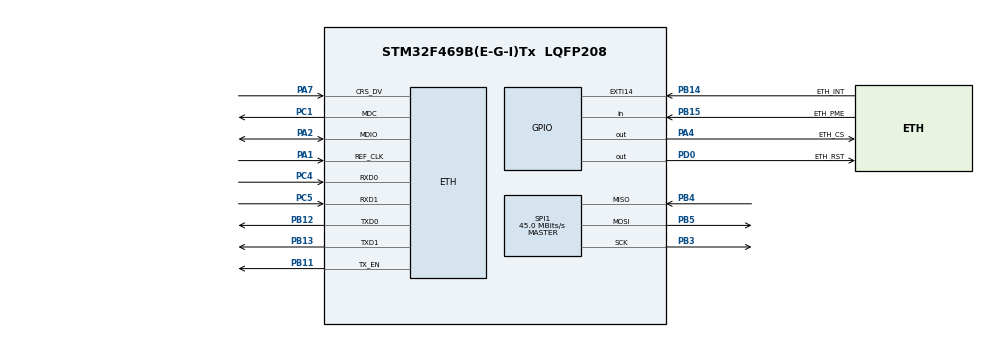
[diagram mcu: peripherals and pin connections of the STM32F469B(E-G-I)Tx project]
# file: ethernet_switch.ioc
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ETH.MediaInterface=HAL_ETH_RMII_MODE
ETH.RxMode=ETH_RXINTERRUPT_MODE
Mcu.Family=STM32F4
Mcu.Name=STM32F469B(E-G-I)Tx
Mcu.Package=LQFP208
NVIC.ETH_IRQn=true\:0\:0\:false\:false\:true\:true\:true\:true
NVIC.PriorityGroup=NVIC_PRIORITYGROUP_4
PA1.Mode=RMII
PA1.Signal=ETH_REF_CLK
PA2.Mode=RMII
PA2.Signal=ETH_MDIO
PA4.GPIO_Label=ETH_CS
PA4.GPIO_Speed=GPIO_SPEED_FREQ_VERY_HIGH
PA4.PinState=GPIO_PIN_SET
PA4.Signal=GPIO_Output
PA7.Mode=RMII
PA7.Signal=ETH_CRS_DV
PB11.Mode=RMII
PB11.Signal=ETH_TX_EN
PB12.Mode=RMII
PB12.Signal=ETH_TXD0
PB13.Mode=RMII
PB13.Signal=ETH_TXD1
PB14.GPIO_Label=ETH_INT
PB14.Signal=GPXTI14
PB15.GPIO_Label=ETH_PME
PB15.Signal=GPIO_Input
PB3.Mode=Full_Duplex_Master
PB3.Signal=SPI1_SCK
PB4.Mode=Full_Duplex_Master
PB4.Signal=SPI1_MISO
PB5.Mode=Full_Duplex_Master
PB5.Signal=SPI1_MOSI
PC1.Mode=RMII
PC1.Signal=ETH_MDC
PC4.Mode=RMII
PC4.Signal=ETH_RXD0
PC5.Mode=RMII
PC5.Signal=ETH_RXD1
PD0.GPIO_Label=ETH_RST
PD0.Signal=GPIO_Output
ProjectManager.HeapSize=0x200
ProjectManager.StackSize=0x400
ProjectManager.TargetToolchain=EWARM V8.50
RCC.AHBFreq_Value=180000000
RCC.APB1CLKDivider=RCC_HCLK_DIV4
RCC.APB1Freq_Value=45000000
RCC.APB1TimFreq_Value=90000000
RCC.APB2CLKDivider=RCC_HCLK_DIV2
RCC.APB2Freq_Value=90000000
RCC.APB2TimFreq_Value=180000000
RCC.CortexFreq_Value=180000000
RCC.HCLKFreq_Value=180000000
RCC.PLLM=8
RCC.PLLN=180
RCC.SYSCLKFreq_VALUE=180000000
RCC.SYSCLKSource=RCC_SYSCLKSOURCE_PLLCLK
RCC.USBFreq_Value=90000000
RCC.VCOOutputFreq_Value=360000000
SPI1.CalculateBaudRate=45.0 MBits/s
SPI1.Direction=SPI_DIRECTION_2LINES
SPI1.Mode=SPI_MODE_MASTER
SPI1.VirtualType=VM_MASTER
board=custom

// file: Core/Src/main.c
/* USER CODE BEGIN Header */
/**
  ******************************************************************************
  * @file           : main.c
  * @brief          : Main program body
  ******************************************************************************
  * @attention
  *
  * Copyright (c) 2026 STMicroelectronics.
  * All rights reserved.
  *
  * This software is licensed under terms that can be found in the LICENSE file
  * in the root directory of this software component.
  * If no LICENSE file comes with this software, it is provided AS-IS.
  *
  ******************************************************************************
  */
/* USER CODE END Header */
#include "main.h"
#include "cmsis_os.h"
#include "lwip.h"
#include "usb_device.h"

/* USER CODE BEGIN Includes */
#include "kszspi.h"
#include "config.h"
/* USER CODE END Includes */

/* USER CODE BEGIN PD */
#define MIB_RX_BYTE_CNT 0x80
#define MIB_TX_BYTE_CNT 0x81
/* USER CODE END PD */

SPI_HandleTypeDef hspi1;
DMA_HandleTypeDef hdma_spi1_tx;
DMA_HandleTypeDef hdma_spi1_rx;

osThreadId MainTaskHandle;
osThreadId WebUITaskHandle;
osThreadId MQTTTaskHandle;
osMessageQId mqttPublishQueueHandle;

void SystemClock_Config(void);
static void MX_GPIO_Init(void);
static void MX_DMA_Init(void);
static void MX_SPI1_Init(void);
void StartDefaultTask(void const * argument);
void StartTask02(void const * argument);
void StartTask03(void const * argument);

int main(void)
{

  /* MCU Configuration--------------------------------------------------------*/

  /* Reset of all peripherals, Initializes the Flash interface and the Systick. */
  HAL_Init();

  /* Configure the system clock */
  SystemClock_Config();

  /* Initialize all configured peripherals */
  MX_GPIO_Init();
  MX_DMA_Init();
  MX_SPI1_Init();
  /* USER CODE BEGIN 2 */
  Config_Init();
  /* USER CODE END 2 */

  /* Create the queue(s) */
  /* definition and creation of mqttPublishQueue */
  osMessageQDef(mqttPublishQueue, 16, uint32_t);
  mqttPublishQueueHandle = osMessageCreate(osMessageQ(mqttPublishQueue), NULL);

  /* Create the thread(s) */
  /* definition and creation of MainTask */
  osThreadDef(MainTask, StartDefaultTask, osPriorityNormal, 0, 256);
  MainTaskHandle = osThreadCreate(osThread(MainTask), NULL);

  /* definition and creation of WebUITask */
  osThreadDef(WebUITask, StartTask02, osPriorityIdle, 0, 1024);
  WebUITaskHandle = osThreadCreate(osThread(WebUITask), NULL);

  /* definition and creation of MQTTTask */
  osThreadDef(MQTTTask, StartTask03, osPriorityIdle, 0, 2048);
  MQTTTaskHandle = osThreadCreate(osThread(MQTTTask), NULL);

  /* Start scheduler */
  osKernelStart();

  /* We should never get here as control is now taken by the scheduler */

  /* Infinite loop */
  while (1)
  {

  }
}

void SystemClock_Config(void)
{
  RCC_OscInitTypeDef RCC_OscInitStruct = {0};
  RCC_ClkInitTypeDef RCC_ClkInitStruct = {0};

  /** Configure the main internal regulator output voltage
  */
  __HAL_RCC_PWR_CLK_ENABLE();
  __HAL_PWR_VOLTAGESCALING_CONFIG(PWR_REGULATOR_VOLTAGE_SCALE3);

  /** Initializes the RCC Oscillators according to the specified parameters
  * in the RCC_OscInitTypeDef structure.
  */
  RCC_OscInitStruct.OscillatorType = RCC_OSCILLATORTYPE_HSE;
  RCC_OscInitStruct.HSEState = RCC_HSE_BYPASS;
  RCC_OscInitStruct.PLL.PLLState = RCC_PLL_ON;
  RCC_OscInitStruct.PLL.PLLSource = RCC_PLLSOURCE_HSE;
  RCC_OscInitStruct.PLL.PLLM = 15;
  RCC_OscInitStruct.PLL.PLLN = 144;
  RCC_OscInitStruct.PLL.PLLP = RCC_PLLP_DIV2;
  RCC_OscInitStruct.PLL.PLLQ = 5;
  RCC_OscInitStruct.PLL.PLLR = 2;
  if (HAL_RCC_OscConfig(&RCC_OscInitStruct) != HAL_OK)
  {
    Error_Handler();
  }

  /** Initializes the CPU, AHB and APB buses clocks
  */
  RCC_ClkInitStruct.ClockType = RCC_CLOCKTYPE_HCLK|RCC_CLOCKTYPE_SYSCLK
                              |RCC_CLOCKTYPE_PCLK1|RCC_CLOCKTYPE_PCLK2;
  RCC_ClkInitStruct.SYSCLKSource = RCC_SYSCLKSOURCE_PLLCLK;
  RCC_ClkInitStruct.AHBCLKDivider = RCC_SYSCLK_DIV1;
  RCC_ClkInitStruct.APB1CLKDivider = RCC_HCLK_DIV4;
  RCC_ClkInitStruct.APB2CLKDivider = RCC_HCLK_DIV2;

  if (HAL_RCC_ClockConfig(&RCC_ClkInitStruct, FLASH_LATENCY_3) != HAL_OK)
  {
    Error_Handler();
  }
}

static void MX_SPI1_Init(void)
{

  /* SPI1 parameter configuration*/
  hspi1.Instance = SPI1;
  hspi1.Init.Mode = SPI_MODE_MASTER;
  hspi1.Init.Direction = SPI_DIRECTION_2LINES;
  hspi1.Init.DataSize = SPI_DATASIZE_8BIT;
  hspi1.Init.CLKPolarity = SPI_POLARITY_LOW;
  hspi1.Init.CLKPhase = SPI_PHASE_1EDGE;
  hspi1.Init.NSS = SPI_NSS_SOFT;
  hspi1.Init.BaudRatePrescaler = SPI_BAUDRATEPRESCALER_2;
  hspi1.Init.FirstBit = SPI_FIRSTBIT_MSB;
  hspi1.Init.TIMode = SPI_TIMODE_DISABLE;
  hspi1.Init.CRCCalculation = SPI_CRCCALCULATION_DISABLE;
  hspi1.Init.CRCPolynomial = 10;
  if (HAL_SPI_Init(&hspi1) != HAL_OK)
  {
    Error_Handler();
  }

}

static void MX_DMA_Init(void)
{

  /* DMA controller clock enable */
  __HAL_RCC_DMA2_CLK_ENABLE();

  /* DMA interrupt init */
  /* DMA2_Stream0_IRQn interrupt configuration */
  HAL_NVIC_SetPriority(DMA2_Stream0_IRQn, 5, 0);
  HAL_NVIC_EnableIRQ(DMA2_Stream0_IRQn);
  /* DMA2_Stream3_IRQn interrupt configuration */
  HAL_NVIC_SetPriority(DMA2_Stream3_IRQn, 5, 0);
  HAL_NVIC_EnableIRQ(DMA2_Stream3_IRQn);

}

static void MX_GPIO_Init(void)
{
  GPIO_InitTypeDef GPIO_InitStruct = {0};

  /* GPIO Ports Clock Enable */
  __HAL_RCC_GPIOE_CLK_ENABLE();
  __HAL_RCC_GPIOI_CLK_ENABLE();
  __HAL_RCC_GPIOC_CLK_ENABLE();
  __HAL_RCC_GPIOF_CLK_ENABLE();
  __HAL_RCC_GPIOH_CLK_ENABLE();
  __HAL_RCC_GPIOA_CLK_ENABLE();
  __HAL_RCC_GPIOB_CLK_ENABLE();
  __HAL_RCC_GPIOJ_CLK_ENABLE();
  __HAL_RCC_GPIOG_CLK_ENABLE();
  __HAL_RCC_GPIOD_CLK_ENABLE();
  __HAL_RCC_GPIOK_CLK_ENABLE();

  /*Configure GPIO pin Output Level */
  HAL_GPIO_WritePin(SPI_CS_GPIO_Port, SPI_CS_Pin, GPIO_PIN_SET);

  /*Configure GPIO pin Output Level */
  HAL_GPIO_WritePin(SW_RST_GPIO_Port, SW_RST_Pin, GPIO_PIN_RESET);

  /*Configure GPIO pins : PE2 PE3 PE4 PE5
                           PE6 PE7 PE8 PE9
                           PE10 PE11 PE12 PE13
                           PE14 PE15 PE0 PE1 */
  GPIO_InitStruct.Pin = GPIO_PIN_2|GPIO_PIN_3|GPIO_PIN_4|GPIO_PIN_5
                          |GPIO_PIN_6|GPIO_PIN_7|GPIO_PIN_8|GPIO_PIN_9
                          |GPIO_PIN_10|GPIO_PIN_11|GPIO_PIN_12|GPIO_PIN_13
                          |GPIO_PIN_14|GPIO_PIN_15|GPIO_PIN_0|GPIO_PIN_1;
  GPIO_InitStruct.Mode = GPIO_MODE_ANALOG;
  GPIO_InitStruct.Pull = GPIO_NOPULL;
  HAL_GPIO_Init(GPIOE, &GPIO_InitStruct);

  /*Configure GPIO pins : PI8 PI9 PI10 PI11
                           PI12 PI13 PI14 PI15
                           PI0 PI1 PI2 PI3
                           PI4 PI5 PI6 PI7 */
  GPIO_InitStruct.Pin = GPIO_PIN_8|GPIO_PIN_9|GPIO_PIN_10|GPIO_PIN_11
                          |GPIO_PIN_12|GPIO_PIN_13|GPIO_PIN_14|GPIO_PIN_15
                          |GPIO_PIN_0|GPIO_PIN_1|GPIO_PIN_2|GPIO_PIN_3
                          |GPIO_PIN_4|GPIO_PIN_5|GPIO_PIN_6|GPIO_PIN_7;
  GPIO_InitStruct.Mode = GPIO_MODE_ANALOG;
  GPIO_InitStruct.Pull = GPIO_NOPULL;
  HAL_GPIO_Init(GPIOI, &GPIO_InitStruct);

  /*Configure GPIO pins : PC13 PC14 PC15 PC0
                           PC2 PC3 PC6 PC7
                           PC8 PC9 PC10 PC11
                           PC12 */
  GPIO_InitStruct.Pin = GPIO_PIN_13|GPIO_PIN_14|GPIO_PIN_15|GPIO_PIN_0
                          |GPIO_PIN_2|GPIO_PIN_3|GPIO_PIN_6|GPIO_PIN_7
                          |GPIO_PIN_8|GPIO_PIN_9|GPIO_PIN_10|GPIO_PIN_11
                          |GPIO_PIN_12;
  GPIO_InitStruct.Mode = GPIO_MODE_ANALOG;
  GPIO_InitStruct.Pull = GPIO_NOPULL;
  HAL_GPIO_Init(GPIOC, &GPIO_InitStruct);

  /*Configure GPIO pins : PF0 PF1 PF2 PF3
                           PF4 PF5 PF6 PF7
                           PF8 PF9 PF10 PF11
                           PF12 PF13 PF14 PF15 */
  GPIO_InitStruct.Pin = GPIO_PIN_0|GPIO_PIN_1|GPIO_PIN_2|GPIO_PIN_3
                          |GPIO_PIN_4|GPIO_PIN_5|GPIO_PIN_6|GPIO_PIN_7
                          |GPIO_PIN_8|GPIO_PIN_9|GPIO_PIN_10|GPIO_PIN_11
                          |GPIO_PIN_12|GPIO_PIN_13|GPIO_PIN_14|GPIO_PIN_15;
  GPIO_InitStruct.Mode = GPIO_MODE_ANALOG;
  GPIO_InitStruct.Pull = GPIO_NOPULL;
  HAL_GPIO_Init(GPIOF, &GPIO_InitStruct);

  /*Configure GPIO pins : PA0 PA3 PA5 PA6
                           PA8 PA9 PA10 PA13
                           PA14 PA15 */
  GPIO_InitStruct.Pin = GPIO_PIN_0|GPIO_PIN_3|GPIO_PIN_5|GPIO_PIN_6
                          |GPIO_PIN_8|GPIO_PIN_9|GPIO_PIN_10|GPIO_PIN_13
                          |GPIO_PIN_14|GPIO_PIN_15;
  GPIO_InitStruct.Mode = GPIO_MODE_ANALOG;
  GPIO_InitStruct.Pull = GPIO_NOPULL;
  HAL_GPIO_Init(GPIOA, &GPIO_InitStruct);

  /*Configure GPIO pins : PH2 PH3 PH4 PH5
                           PH6 PH7 PH8 PH9
                           PH10 PH11 PH12 PH13
                           PH14 PH15 */
  GPIO_InitStruct.Pin = GPIO_PIN_2|GPIO_PIN_3|GPIO_PIN_4|GPIO_PIN_5
                          |GPIO_PIN_6|GPIO_PIN_7|GPIO_PIN_8|GPIO_PIN_9
                          |GPIO_PIN_10|GPIO_PIN_11|GPIO_PIN_12|GPIO_PIN_13
                          |GPIO_PIN_14|GPIO_PIN_15;
  GPIO_InitStruct.Mode = GPIO_MODE_ANALOG;
  GPIO_InitStruct.Pull = GPIO_NOPULL;
  HAL_GPIO_Init(GPIOH, &GPIO_InitStruct);

  /*Configure GPIO pin : SPI_CS_Pin */
  GPIO_InitStruct.Pin = SPI_CS_Pin;
  GPIO_InitStruct.Mode = GPIO_MODE_OUTPUT_PP;
  GPIO_InitStruct.Pull = GPIO_NOPULL;
  GPIO_InitStruct.Speed = GPIO_SPEED_FREQ_VERY_HIGH;
  HAL_GPIO_Init(SPI_CS_GPIO_Port, &GPIO_InitStruct);

  /*Configure GPIO pins : PB0 PB1 PB2 PB10
                           PB6 PB7 PB8 PB9 */
  GPIO_InitStruct.Pin = GPIO_PIN_0|GPIO_PIN_1|GPIO_PIN_2|GPIO_PIN_10
                          |GPIO_PIN_6|GPIO_PIN_7|GPIO_PIN_8|GPIO_PIN_9;
  GPIO_InitStruct.Mode = GPIO_MODE_ANALOG;
  GPIO_InitStruct.Pull = GPIO_NOPULL;
  HAL_GPIO_Init(GPIOB, &GPIO_InitStruct);

  /*Configure GPIO pins : PJ0 PJ1 PJ2 PJ3
                           PJ4 PJ5 PJ12 PJ13
                           PJ14 PJ15 */
  GPIO_InitStruct.Pin = GPIO_PIN_0|GPIO_PIN_1|GPIO_PIN_2|GPIO_PIN_3
                          |GPIO_PIN_4|GPIO_PIN_5|GPIO_PIN_12|GPIO_PIN_13
                          |GPIO_PIN_14|GPIO_PIN_15;
  GPIO_InitStruct.Mode = GPIO_MODE_ANALOG;
  GPIO_InitStruct.Pull = GPIO_NOPULL;
  HAL_GPIO_Init(GPIOJ, &GPIO_InitStruct);

  /*Configure GPIO pins : PG0 PG1 PG2 PG3
                           PG4 PG5 PG6 PG7
                           PG8 PG9 PG10 PG11
                           PG12 PG13 PG14 PG15 */
  GPIO_InitStruct.Pin = GPIO_PIN_0|GPIO_PIN_1|GPIO_PIN_2|GPIO_PIN_3
                          |GPIO_PIN_4|GPIO_PIN_5|GPIO_PIN_6|GPIO_PIN_7
                          |GPIO_PIN_8|GPIO_PIN_9|GPIO_PIN_10|GPIO_PIN_11
                          |GPIO_PIN_12|GPIO_PIN_13|GPIO_PIN_14|GPIO_PIN_15;
  GPIO_InitStruct.Mode = GPIO_MODE_ANALOG;
  GPIO_InitStruct.Pull = GPIO_NOPULL;
  HAL_GPIO_Init(GPIOG, &GPIO_InitStruct);

  /*Configure GPIO pin : SW_INT_Pin */
  GPIO_InitStruct.Pin = SW_INT_Pin;
  GPIO_InitStruct.Mode = GPIO_MODE_IT_RISING;
  GPIO_InitStruct.Pull = GPIO_NOPULL;
  HAL_GPIO_Init(SW_INT_GPIO_Port, &GPIO_InitStruct);

  /*Configure GPIO pin : SW_PME_Pin */
  GPIO_InitStruct.Pin = SW_PME_Pin;
  GPIO_InitStruct.Mode = GPIO_MODE_INPUT;
  GPIO_InitStruct.Pull = GPIO_NOPULL;
  HAL_GPIO_Init(SW_PME_GPIO_Port, &GPIO_InitStruct);

  /*Configure GPIO pins : PD8 PD9 PD10 PD11
                           PD12 PD13 PD14 PD15
                           PD1 PD2 PD3 PD4
                           PD5 PD6 PD7 */
  GPIO_InitStruct.Pin = GPIO_PIN_8|GPIO_PIN_9|GPIO_PIN_10|GPIO_PIN_11
                          |GPIO_PIN_12|GPIO_PIN_13|GPIO_PIN_14|GPIO_PIN_15
                          |GPIO_PIN_1|GPIO_PIN_2|GPIO_PIN_3|GPIO_PIN_4
                          |GPIO_PIN_5|GPIO_PIN_6|GPIO_PIN_7;
  GPIO_InitStruct.Mode = GPIO_MODE_ANALOG;
  GPIO_InitStruct.Pull = GPIO_NOPULL;
  HAL_GPIO_Init(GPIOD, &GPIO_InitStruct);

  /*Configure GPIO pin : SW_RST_Pin */
  GPIO_InitStruct.Pin = SW_RST_Pin;
  GPIO_InitStruct.Mode = GPIO_MODE_OUTPUT_PP;
  GPIO_InitStruct.Pull = GPIO_NOPULL;
  GPIO_InitStruct.Speed = GPIO_SPEED_FREQ_LOW;
  HAL_GPIO_Init(SW_RST_GPIO_Port, &GPIO_InitStruct);

  /*Configure GPIO pins : PK3 PK4 PK5 PK6
                           PK7 */
  GPIO_InitStruct.Pin = GPIO_PIN_3|GPIO_PIN_4|GPIO_PIN_5|GPIO_PIN_6
                          |GPIO_PIN_7;
  GPIO_InitStruct.Mode = GPIO_MODE_ANALOG;
  GPIO_InitStruct.Pull = GPIO_NOPULL;
  HAL_GPIO_Init(GPIOK, &GPIO_InitStruct);

}

void StartDefaultTask(void const * argument)
{
  /* init code for USB_DEVICE */
  MX_USB_DEVICE_Init();

  /* init code for LWIP */
  MX_LWIP_Init();
  /* USER CODE BEGIN 5 */
  if (KSZ_SPI_Init() == 1) {

  } else {

  }

  uint16_t speed = 0;
  uint8_t duplex = 0;
  uint8_t link_status = 0;
  uint64_t rx_bytes = 0;
  uint64_t tx_bytes = 0;

  /* Infinite loop */
  for(;;)
  {

    char *json_buffer = (char *)pvPortMalloc(512);

    if (json_buffer != NULL) {
      int offset = 0;

      offset += snprintf(json_buffer + offset, sizeof(json_buffer) - offset, "{");

      for (int i = 1; i < 8; i++) {
        link_status = KSZ_GetPortStatus(i, &speed, &duplex);
        if (link_status == 1) {
          rx_bytes = KSZ_ReadMIB(i, MIB_RX_BYTE_CNT);
          tx_bytes = KSZ_ReadMIB(i, MIB_TX_BYTE_CNT);
        } else {
          rx_bytes = 0;
          tx_bytes = 0;
        }
        offset += snprintf(json_buffer + offset, sizeof(json_buffer) - offset,
                     "\"port_%d\":{\"link\":%d,\"speed\":%d,\"duplex\":%d,\"rx\":%llu,\"tx\":%llu}%s",
                     i, link_status, speed, duplex, rx_bytes, tx_bytes,
                     (i == 7) ? "" : ",");
      }
      snprintf(json_buffer + offset, sizeof(json_buffer) - offset, "}");

      char *pointer_to_send = json_buffer;

      if (xQueueSend(mqttPublishQueueHandle, &json_buffer, pdMS_TO_TICKS(10)) != pdPASS) {
        vPortFree(json_buffer);
      }
    }

    osDelay(1000);
  }
  /* USER CODE END 5 */
}

void StartTask02(void const * argument)
{
  for(;;)
  {
    osDelay(1);
  }
}

void StartTask03(void const * argument)
{
  /* USER CODE BEGIN StartTask03 */
  mqtt_client_t *client = mqtt_client_new();

  ip_addr_t broker_ip;
  struct mqtt_connect_client_info_t ci;

  memset(&ci, 0, sizeof(ci));
  ci.client_id = "stm32_switch";
  ci.keep_alive = 60;

  char *received_json = NULL;

  /* Infinite loop */
  for(;;)
  {
    if (xQueueReceive(mqttPublishQueueHandle, &received_json, portMAX_DELAY) == pdPASS)
    {
      if (client != NULL) {
        ipaddr_aton(CurrentConfig.mqtt_broker_ip, &broker_ip);
        if (!mqtt_client_is_connected(client)) {
          mqtt_client_connect(client, &broker_ip, 1883, NULL, NULL, &ci);

          osDelay(200);
        }

        if (mqtt_client_is_connected(client))
        {
          mqtt_publish(client,
                       "homeassistant/sensor/ksz9477/state",
                       received_json,
                       strlen(received_json),
                       0, 0, NULL, NULL);
        }
      }

      vPortFree(received_json);
    }
  }
  /* USER CODE END StartTask03 */
}

void HAL_TIM_PeriodElapsedCallback(TIM_HandleTypeDef *htim)
{
  if (htim->Instance == TIM6)
  {
    HAL_IncTick();
  }
}

void Error_Handler(void)
{
  __disable_irq();
  while (1)
  {
  }
}
